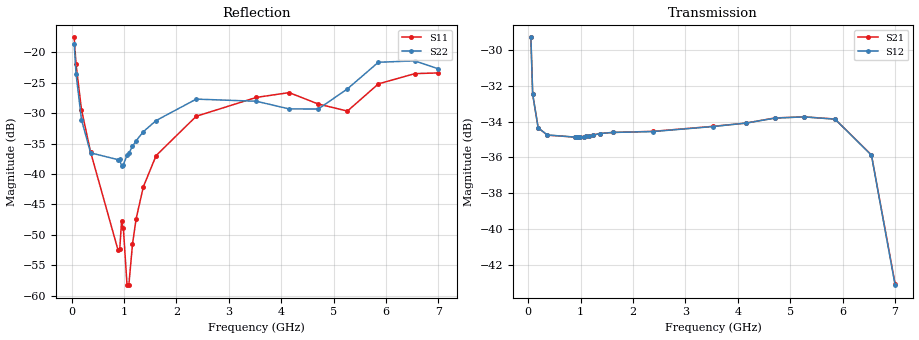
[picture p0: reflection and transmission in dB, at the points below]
! Integrated Device Technology
! Corporate Headquarters
! 6024 Silver Creek Valley Road
! San Jose, CA 95138  USA
! Phone:  1-408-284-8200
! Toll Free:  1-800-223-1366
! Webpage:  http://www.idt.com/
! Timing and RF Division
! 515 Groton Road, Suite 102
! Westford, MA 01886-6024
! Device:  F2258
! Description: Voltage Variable RF Attenuator
! Frequency:  50.0 -  6000.00 MHz
! Package:  3x3 mm Thin QFN Plastic Package: 16 pin
! Ports:  2 RF, 2 DC
!  Pin  1  = NC
!  Pin  2  = NC
!  Pin  3  = RF2  = Port 2
!  Pin  4  = GND
!  Pin  5  = Vdd
!  Pin  6  = NC
!  Pin  7  = VCTRL
!  Pin  8  = NC
!  Pin  9  = GND
!  Pin 10  = RF1  = Port 1
!  Pin 11  = NC
!  Pin 12  = NC
!  Pin 13  = NC
!  Pin 14  = NC
!  Pin 15  = NC
!  Pin 16  = NC
! Vcntrl:  1.970 Volts
! Vdd:  +3.300 Volts
! Current:  1.153 mA
! Data:  The device was measured on a the F2258 evaluation board which has
!  individual transmission lines to the RF pins.  Data was collected
!  using a calibrated network analyzer.  The evaluation board was
!  de-embedded using a TRL calibration technique.
!  The reference plane is the edge of the package pin.
! Misc:  SN 10
!  Action Tracker AT0285
! Date Measured:  2014-12-10
! Date:  2016-01-13  MJV
! Note:
!  Integrated Device Technology supplies this data as a sample of measured
!  data at the package pin for this product.  Your particular data for this
!  product may vary.
!  Data was taken at 25 degrees C.
!  Integrated Device Technology reserves the right to change this data at anytime.
!Freq_(GHz)  S11M_(dB)  S11P_(deg)  S21M_(dB)  S21P_(deg)  S12M_(dB)  S12P_(deg)  S22M_(dB)  S22P_(deg)
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# GHz S dB R 50
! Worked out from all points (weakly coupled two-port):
!   201 points, 50 MHz to 7 GHz, reference 50 ohm
!   highest |S21| = -29.30 dB at 50 MHz (marker M1); lowest = -43.1 dB at 7 GHz (marker M2)
!   lowest |S11| = -58.3 dB at 1.093 GHz (marker M3), VSWR 1.00, Z = 49.9 + j0.109 ohm
!   |S11| at or under -10 dB: start of sweep to end of sweep
!   |S22| runs from -38.7 to -18.6 dB; largest |S21 - S12| = 8.2e-05
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0.05  -17.55 -110.9  -29.30 -66.2  -29.30 -66.2  -18.65 -107.1
0.08475  -21.97 -107.3  -32.48 -46.7  -32.48 -46.8  -23.52 -96.7
0.189  -29.43 -109.3  -34.35 -23.7  -34.35 -23.7  -31.09 -78.2
0.36275  -36.41 -116.9  -34.76 -13.9  -34.75 -13.8  -36.54 -46.3
0.884  -52.45 166.3  -34.87 -8.7  -34.87 -8.7  -37.65 10.9
0.91875  -52.42 149.2  -34.87 -8.7  -34.87 -8.6  -37.59 12.1
0.9535  -47.79 -161.7  -34.88 -8.6  -34.88 -8.6  -38.72 26.5
0.98825  -48.96 -173.6  -34.86 -8.5  -34.86 -8.5  -38.46 23.9
1.05775  -58.25 154.5  -34.84 -8.4  -34.85 -8.4  -36.94 23.4
1.0925  -58.28 116.3  -34.83 -8.4  -34.83 -8.4  -36.61 23.3
1.162  -51.58 68.1  -34.80 -8.4  -34.81 -8.4  -35.46 22.3
1.2315  -47.36 45.1  -34.76 -8.5  -34.77 -8.5  -34.55 21.2
1.3705  -42.08 36.3  -34.67 -9.0  -34.67 -9.0  -33.04 20.7
1.61375  -36.97 32.5  -34.61 -10.4  -34.61 -10.4  -31.22 18.7
2.37825  -30.52 47.9  -34.55 -14.3  -34.56 -14.2  -27.70 21.1
3.525  -27.42 91.5  -34.27 -21.1  -34.28 -21.1  -28.05 47.4
4.1505  -26.63 104.9  -34.09 -25.6  -34.09 -25.7  -29.31 57.6
4.7065  -28.50 95.5  -33.80 -30.4  -33.81 -30.4  -29.33 38.7
5.2625  -29.67 54.2  -33.74 -36.5  -33.74 -36.6  -26.02 4.0
5.85325  -25.20 29.8  -33.86 -46.9  -33.87 -46.9  -21.64 -12.9
6.54825  -23.51 45.0  -35.87 -66.7  -35.88 -66.8  -21.41 -46.1
7  -23.39 84.4  -43.07 -62.9  -43.14 -62.4  -22.73 -127.4
